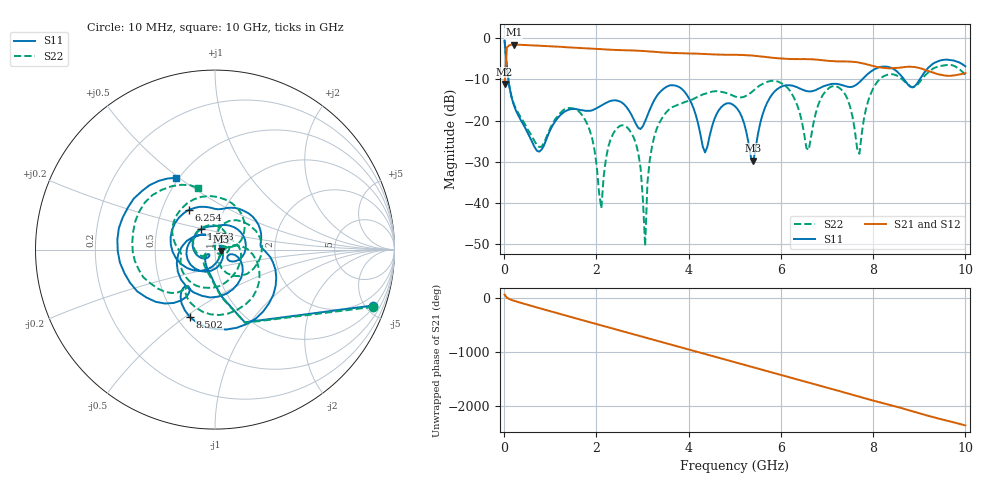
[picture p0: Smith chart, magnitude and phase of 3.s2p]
!Agilent Technologies,N5230C,MY49000813,A.09.42.22
!Agilent N5230C: A.09.42.22
!Date: Friday, August 21, 2026 19:34:15
!Correction: S11(Full 2 Port(1,2))
!S21(Full 2 Port(1,2))
!S12(Full 2 Port(1,2))
!S22(Full 2 Port(1,2))
!S2P File: Measurements: S11, S21, S12, S22:
# Hz S  dB  R 50
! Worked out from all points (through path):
!   201 points, 10 MHz to 10 GHz, reference 50 ohm
!   highest |S21| = -1.59 dB at 209.8 MHz (marker M1); lowest = -11.1 dB at 10 MHz (marker M2)
!   lowest |S11| = -29.7 dB at 5.405 GHz (marker M3), VSWR 1.07, Z = 53.3 - j0.748 ohm
!   |S11| at or under -10 dB: 91.98 MHz to 7.764 GHz (7.672 GHz wide, 195 % of centre); 8.669 GHz to 9.012 GHz (343.2 MHz wide, 3.88 % of centre)
!   |S22| runs from -50.5 to -0.6 dB; largest |S21 - S12| = 0.0051
!   S11 on the Smith chart (normalised r, x): 10 MHz: 1.18, -5.56; 1.558 GHz: 0.83, +0.19; 6.254 GHz: 0.68, +0.33; 8.502 GHz: 0.58, -0.52; 10 GHz: 0.48, +0.49
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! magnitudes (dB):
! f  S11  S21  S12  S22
! 10 MHz  -0.6  -11.1  -11.3  -0.6
! 209.8 MHz  -16.2  -1.6  -1.6  -16.0
! 759.2 MHz  -27.5  -1.8  -1.8  -26.4
! 1.558 GHz  -17.2  -2.4  -2.4  -17.3
! 1.708 GHz  -17.5  -2.5  -2.4  -19.0
! 2.108 GHz  -16.3  -2.7  -2.7  -41.3
! 2.308 GHz  -15.2  -2.8  -2.8  -24.5
! 2.807 GHz  -19.6  -3.0  -3.0  -24.1
! 2.957 GHz  -22.1  -3.1  -3.1  -31.4
! 3.057 GHz  -20.1  -3.1  -3.2  -50.5
! 3.157 GHz  -17.4  -3.2  -3.3  -29.6
! 3.357 GHz  -13.4  -3.4  -3.4  -20.7
! 4.356 GHz  -27.7  -3.9  -3.9  -13.5
! 5.005 GHz  -16.6  -4.1  -4.1  -14.2
! 5.405 GHz  -29.7  -4.2  -4.3  -12.7
! 6.254 GHz  -11.5  -5.1  -5.1  -13.9
! 6.703 GHz  -12.8  -5.1  -5.2  -20.8
! 7.253 GHz  -11.2  -5.7  -5.7  -12.0
! 7.702 GHz  -10.7  -6.0  -5.9  -28.1
! 8.352 GHz  -7.1  -7.3  -7.3  -8.8
! 8.502 GHz  -7.9  -7.2  -7.3  -9.0
! 10 GHz  -6.8  -8.5  -8.5  -9.0
